VERSION 5.7 ;
  NOWIREEXTENSIONATPIN ON ;
  DIVIDERCHAR "/" ;
  BUSBITCHARS "[]" ;
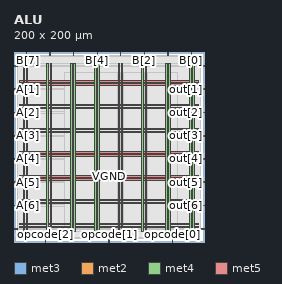
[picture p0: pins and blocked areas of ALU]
MACRO ALU
  CLASS BLOCK ;
  FOREIGN ALU ;
  ORIGIN 0.000 0.000 ;
  SIZE 200.000 BY 200.000 ;
  PIN A[0]
    DIRECTION INPUT ;
    USE SIGNAL ;
    ANTENNAGATEAREA 0.495000 ;
    PORT
      LAYER met3 ;
        RECT 0.000 185.000 4.000 185.600 ;
    END
  END A[0]
  PIN A[1]
    DIRECTION INPUT ;
    USE SIGNAL ;
    ANTENNAGATEAREA 0.742500 ;
    PORT
      LAYER met3 ;
        RECT 0.000 160.520 4.000 161.120 ;
    END
  END A[1]
  PIN A[2]
    DIRECTION INPUT ;
    USE SIGNAL ;
    ANTENNAGATEAREA 0.495000 ;
    PORT
      LAYER met3 ;
        RECT 0.000 136.040 4.000 136.640 ;
    END
  END A[2]
  PIN A[3]
    DIRECTION INPUT ;
    USE SIGNAL ;
    ANTENNAGATEAREA 0.495000 ;
    PORT
      LAYER met3 ;
        RECT 0.000 111.560 4.000 112.160 ;
    END
  END A[3]
  PIN A[4]
    DIRECTION INPUT ;
    USE SIGNAL ;
    ANTENNAGATEAREA 0.247500 ;
    PORT
      LAYER met3 ;
        RECT 0.000 87.080 4.000 87.680 ;
    END
  END A[4]
  PIN A[5]
    DIRECTION INPUT ;
    USE SIGNAL ;
    ANTENNAGATEAREA 0.247500 ;
    PORT
      LAYER met3 ;
        RECT 0.000 62.600 4.000 63.200 ;
    END
  END A[5]
  PIN A[6]
    DIRECTION INPUT ;
    USE SIGNAL ;
    ANTENNAGATEAREA 0.742500 ;
    PORT
      LAYER met3 ;
        RECT 0.000 38.120 4.000 38.720 ;
    END
  END A[6]
  PIN A[7]
    DIRECTION INPUT ;
    USE SIGNAL ;
    ANTENNAGATEAREA 0.247500 ;
    PORT
      LAYER met3 ;
        RECT 0.000 13.640 4.000 14.240 ;
    END
  END A[7]
  PIN B[0]
    DIRECTION INPUT ;
    USE SIGNAL ;
    ANTENNAGATEAREA 0.742500 ;
    PORT
      LAYER met2 ;
        RECT 186.850 196.000 187.130 200.000 ;
    END
  END B[0]
  PIN B[1]
    DIRECTION INPUT ;
    USE SIGNAL ;
    ANTENNAGATEAREA 0.990000 ;
    PORT
      LAYER met2 ;
        RECT 162.010 196.000 162.290 200.000 ;
    END
  END B[1]
  PIN B[2]
    DIRECTION INPUT ;
    USE SIGNAL ;
    ANTENNAGATEAREA 0.247500 ;
    PORT
      LAYER met2 ;
        RECT 137.170 196.000 137.450 200.000 ;
    END
  END B[2]
  PIN B[3]
    DIRECTION INPUT ;
    USE SIGNAL ;
    ANTENNAGATEAREA 0.247500 ;
    PORT
      LAYER met2 ;
        RECT 112.330 196.000 112.610 200.000 ;
    END
  END B[3]
  PIN B[4]
    DIRECTION INPUT ;
    USE SIGNAL ;
    ANTENNAGATEAREA 0.247500 ;
    PORT
      LAYER met2 ;
        RECT 87.490 196.000 87.770 200.000 ;
    END
  END B[4]
  PIN B[5]
    DIRECTION INPUT ;
    USE SIGNAL ;
    ANTENNAGATEAREA 0.742500 ;
    PORT
      LAYER met2 ;
        RECT 62.650 196.000 62.930 200.000 ;
    END
  END B[5]
  PIN B[6]
    DIRECTION INPUT ;
    USE SIGNAL ;
    ANTENNAGATEAREA 0.495000 ;
    PORT
      LAYER met2 ;
        RECT 37.810 196.000 38.090 200.000 ;
    END
  END B[6]
  PIN B[7]
    DIRECTION INPUT ;
    USE SIGNAL ;
    ANTENNAGATEAREA 0.213000 ;
    PORT
      LAYER met2 ;
        RECT 12.970 196.000 13.250 200.000 ;
    END
  END B[7]
  PIN VGND
    DIRECTION INOUT ;
    USE GROUND ;
    PORT
      LAYER met4 ;
        RECT 13.020 10.640 14.620 187.920 ;
    END
    PORT
      LAYER met4 ;
        RECT 38.020 10.640 39.620 187.920 ;
    END
    PORT
      LAYER met4 ;
        RECT 63.020 10.640 64.620 187.920 ;
    END
    PORT
      LAYER met4 ;
        RECT 88.020 10.640 89.620 187.920 ;
    END
    PORT
      LAYER met4 ;
        RECT 113.020 10.640 114.620 187.920 ;
    END
    PORT
      LAYER met4 ;
        RECT 138.020 10.640 139.620 187.920 ;
    END
    PORT
      LAYER met4 ;
        RECT 163.020 10.640 164.620 187.920 ;
    END
    PORT
      LAYER met4 ;
        RECT 188.020 10.640 189.620 187.920 ;
    END
    PORT
      LAYER met5 ;
        RECT 5.280 18.380 194.360 19.980 ;
    END
    PORT
      LAYER met5 ;
        RECT 5.280 43.380 194.360 44.980 ;
    END
    PORT
      LAYER met5 ;
        RECT 5.280 68.380 194.360 69.980 ;
    END
    PORT
      LAYER met5 ;
        RECT 5.280 93.380 194.360 94.980 ;
    END
    PORT
      LAYER met5 ;
        RECT 5.280 118.380 194.360 119.980 ;
    END
    PORT
      LAYER met5 ;
        RECT 5.280 143.380 194.360 144.980 ;
    END
    PORT
      LAYER met5 ;
        RECT 5.280 168.380 194.360 169.980 ;
    END
  END VGND
  PIN VPWR
    DIRECTION INOUT ;
    USE POWER ;
    PORT
      LAYER met4 ;
        RECT 9.720 10.640 11.320 187.920 ;
    END
    PORT
      LAYER met4 ;
        RECT 34.720 10.640 36.320 187.920 ;
    END
    PORT
      LAYER met4 ;
        RECT 59.720 10.640 61.320 187.920 ;
    END
    PORT
      LAYER met4 ;
        RECT 84.720 10.640 86.320 187.920 ;
    END
    PORT
      LAYER met4 ;
        RECT 109.720 10.640 111.320 187.920 ;
    END
    PORT
      LAYER met4 ;
        RECT 134.720 10.640 136.320 187.920 ;
    END
    PORT
      LAYER met4 ;
        RECT 159.720 10.640 161.320 187.920 ;
    END
    PORT
      LAYER met4 ;
        RECT 184.720 10.640 186.320 187.920 ;
    END
    PORT
      LAYER met5 ;
        RECT 5.280 15.080 194.360 16.680 ;
    END
    PORT
      LAYER met5 ;
        RECT 5.280 40.080 194.360 41.680 ;
    END
    PORT
      LAYER met5 ;
        RECT 5.280 65.080 194.360 66.680 ;
    END
    PORT
      LAYER met5 ;
        RECT 5.280 90.080 194.360 91.680 ;
    END
    PORT
      LAYER met5 ;
        RECT 5.280 115.080 194.360 116.680 ;
    END
    PORT
      LAYER met5 ;
        RECT 5.280 140.080 194.360 141.680 ;
    END
    PORT
      LAYER met5 ;
        RECT 5.280 165.080 194.360 166.680 ;
    END
  END VPWR
  PIN opcode[0]
    DIRECTION INPUT ;
    USE SIGNAL ;
    ANTENNAGATEAREA 0.247500 ;
    PORT
      LAYER met2 ;
        RECT 166.610 0.000 166.890 4.000 ;
    END
  END opcode[0]
  PIN opcode[1]
    DIRECTION INPUT ;
    USE SIGNAL ;
    ANTENNAGATEAREA 0.247500 ;
    PORT
      LAYER met2 ;
        RECT 99.910 0.000 100.190 4.000 ;
    END
  END opcode[1]
  PIN opcode[2]
    DIRECTION INPUT ;
    USE SIGNAL ;
    ANTENNAGATEAREA 0.426000 ;
    PORT
      LAYER met2 ;
        RECT 33.210 0.000 33.490 4.000 ;
    END
  END opcode[2]
  PIN out[0]
    DIRECTION OUTPUT ;
    USE SIGNAL ;
    ANTENNADIFFAREA 0.445500 ;
    PORT
      LAYER met3 ;
        RECT 196.000 185.000 200.000 185.600 ;
    END
  END out[0]
  PIN out[1]
    DIRECTION OUTPUT ;
    USE SIGNAL ;
    ANTENNADIFFAREA 0.445500 ;
    PORT
      LAYER met3 ;
        RECT 196.000 160.520 200.000 161.120 ;
    END
  END out[1]
  PIN out[2]
    DIRECTION OUTPUT ;
    USE SIGNAL ;
    ANTENNADIFFAREA 0.445500 ;
    PORT
      LAYER met3 ;
        RECT 196.000 136.040 200.000 136.640 ;
    END
  END out[2]
  PIN out[3]
    DIRECTION OUTPUT ;
    USE SIGNAL ;
    ANTENNADIFFAREA 0.445500 ;
    PORT
      LAYER met3 ;
        RECT 196.000 111.560 200.000 112.160 ;
    END
  END out[3]
  PIN out[4]
    DIRECTION OUTPUT ;
    USE SIGNAL ;
    ANTENNADIFFAREA 0.445500 ;
    PORT
      LAYER met3 ;
        RECT 196.000 87.080 200.000 87.680 ;
    END
  END out[4]
  PIN out[5]
    DIRECTION OUTPUT ;
    USE SIGNAL ;
    ANTENNADIFFAREA 1.336500 ;
    PORT
      LAYER met3 ;
        RECT 196.000 62.600 200.000 63.200 ;
    END
  END out[5]
  PIN out[6]
    DIRECTION OUTPUT ;
    USE SIGNAL ;
    ANTENNADIFFAREA 1.336500 ;
    PORT
      LAYER met3 ;
        RECT 196.000 38.120 200.000 38.720 ;
    END
  END out[6]
  PIN out[7]
    DIRECTION OUTPUT ;
    USE SIGNAL ;
    ANTENNADIFFAREA 1.782000 ;
    PORT
      LAYER met3 ;
        RECT 196.000 13.640 200.000 14.240 ;
    END
  END out[7]
  OBS
      LAYER nwell ;
        RECT 5.330 10.795 194.310 187.870 ;
      LAYER li1 ;
        RECT 5.520 10.795 194.120 187.765 ;
      LAYER met1 ;
        RECT 4.210 10.640 194.120 187.920 ;
      LAYER met2 ;
        RECT 4.230 195.720 12.690 196.000 ;
        RECT 13.530 195.720 37.530 196.000 ;
        RECT 38.370 195.720 62.370 196.000 ;
        RECT 63.210 195.720 87.210 196.000 ;
        RECT 88.050 195.720 112.050 196.000 ;
        RECT 112.890 195.720 136.890 196.000 ;
        RECT 137.730 195.720 161.730 196.000 ;
        RECT 162.570 195.720 186.570 196.000 ;
        RECT 187.410 195.720 192.190 196.000 ;
        RECT 4.230 4.280 192.190 195.720 ;
        RECT 4.230 4.000 32.930 4.280 ;
        RECT 33.770 4.000 99.630 4.280 ;
        RECT 100.470 4.000 166.330 4.280 ;
        RECT 167.170 4.000 192.190 4.280 ;
      LAYER met3 ;
        RECT 3.990 186.000 196.000 187.845 ;
        RECT 4.400 184.600 195.600 186.000 ;
        RECT 3.990 161.520 196.000 184.600 ;
        RECT 4.400 160.120 195.600 161.520 ;
        RECT 3.990 137.040 196.000 160.120 ;
        RECT 4.400 135.640 195.600 137.040 ;
        RECT 3.990 112.560 196.000 135.640 ;
        RECT 4.400 111.160 195.600 112.560 ;
        RECT 3.990 88.080 196.000 111.160 ;
        RECT 4.400 86.680 195.600 88.080 ;
        RECT 3.990 63.600 196.000 86.680 ;
        RECT 4.400 62.200 195.600 63.600 ;
        RECT 3.990 39.120 196.000 62.200 ;
        RECT 4.400 37.720 195.600 39.120 ;
        RECT 3.990 14.640 196.000 37.720 ;
        RECT 4.400 13.240 195.600 14.640 ;
        RECT 3.990 10.715 196.000 13.240 ;
      LAYER met4 ;
        RECT 53.655 15.135 59.320 178.665 ;
        RECT 61.720 15.135 62.620 178.665 ;
        RECT 65.020 15.135 84.320 178.665 ;
        RECT 86.720 15.135 87.620 178.665 ;
        RECT 90.020 15.135 109.320 178.665 ;
        RECT 111.720 15.135 112.620 178.665 ;
        RECT 115.020 15.135 134.320 178.665 ;
        RECT 136.720 15.135 137.620 178.665 ;
        RECT 140.020 15.135 159.320 178.665 ;
        RECT 161.720 15.135 162.620 178.665 ;
        RECT 165.020 15.135 171.745 178.665 ;
  END
END ALU
END LIBRARY

